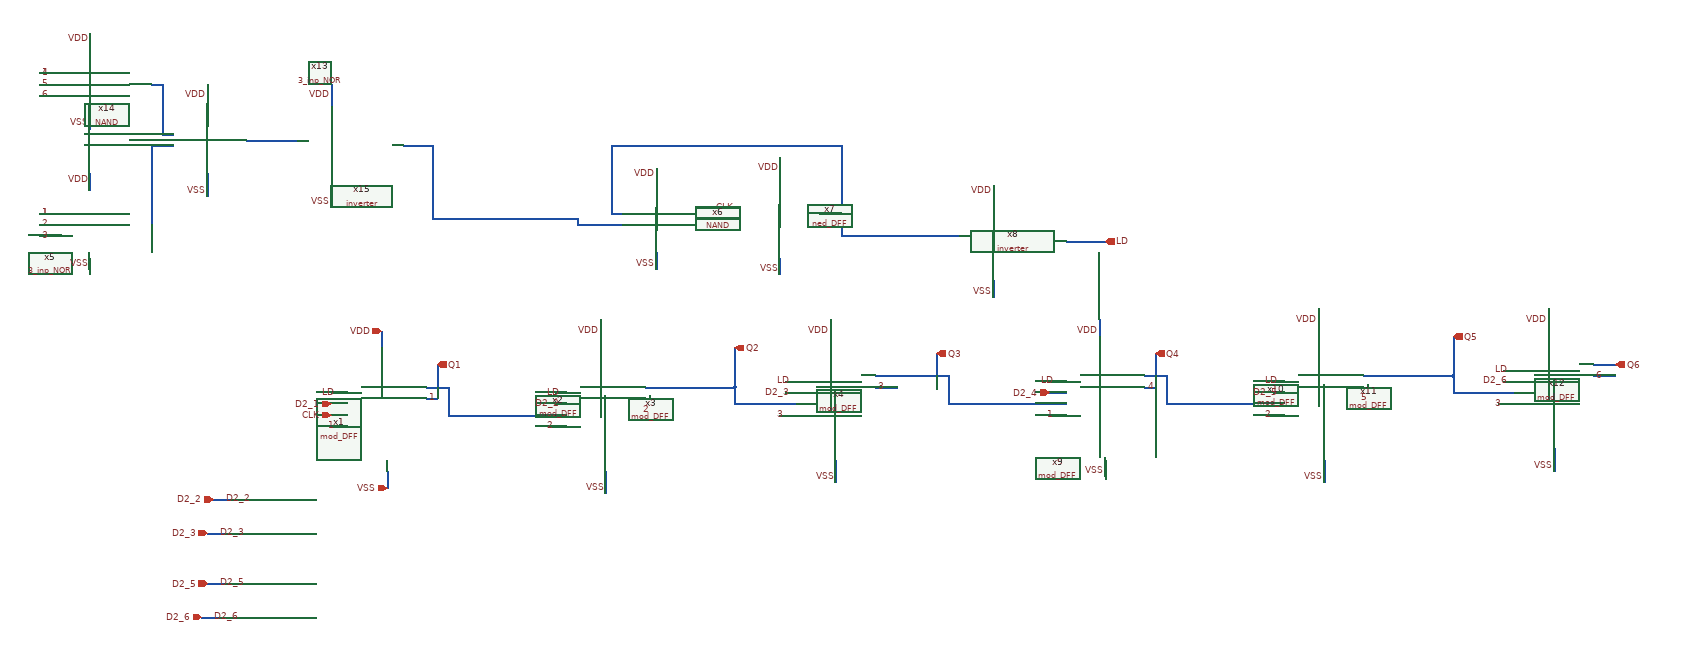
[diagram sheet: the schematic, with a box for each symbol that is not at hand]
v {xschem version=3.1.0 file_version=1.2
}
G {}
K {}
V {}
S {}
E {}
N -280 -100 -260 -100 {
lab=1}
N -450 -50 -420 -50 {
lab=1}
N -450 -90 -420 -90 {
lab=D2_1}
N -450 -70 -420 -70 {
lab=CLK}
N -360 -220 -360 -190 {
lab=VDD}
N -350 30 -350 60 {
lab=VSS}
N -280 -120 -250 -120 {
lab=Q1}
N -250 -120 -240 -120 {
lab=Q1}
N -240 -120 -240 -80 {
lab=Q1}
N -70 -70 -30 -70 {
lab=Q1}
N 860 -380 900 -380 {
lab=LD}
N -450 -110 -420 -110 {
lab=LD}
N -50 -110 -30 -110 {
lab=LD}
N -970 -430 -930 -430 {
lab=1}
N -970 -410 -930 -410 {
lab=2}
N -970 -390 -930 -390 {
lab=3}
N -880 -500 -880 -470 {
lab=VDD}
N -880 -350 -880 -330 {
lab=VSS}
N -10 -410 70 -410 {
lab=#net1}
N 460 -550 460 -390 {
lab=#net2}
N 50 -550 460 -550 {
lab=#net2}
N 50 -550 50 -430 {
lab=#net2}
N 50 -430 70 -430 {
lab=#net2}
N 460 -390 520 -390 {
lab=#net2}
N 350 -530 350 -500 {
lab=VDD}
N 130 -510 130 -480 {
lab=VDD}
N 130 -360 130 -330 {
lab=VSS}
N 350 -350 350 -320 {
lab=VSS}
N 730 -480 730 -450 {
lab=VDD}
N 30 -240 30 -190 {
lab=VDD}
N 340 -90 380 -90 {
lab=Q2}
N 520 -120 560 -120 {
lab=3}
N 110 -100 120 -100 {
lab=2}
N 120 -100 120 -70 {
lab=2}
N 360 -110 380 -110 {
lab=D2_3}
N -50 -90 -30 -90 {
lab=D2_2}
N -260 -160 -260 -120 {
lab=Q1}
N 270 -190 270 -140 {
lab=Q2}
N 520 -140 560 -140 {
lab=Q3}
N -660 80 -630 80 {
lab=D2_2}
N 440 -240 440 -210 {
lab=VDD}
N 450 10 450 50 {
lab=VSS}
N -670 140 -640 140 {
lab=D2_3}
N -60 -50 -30 -50 {
lab=2}
N 350 -70 380 -70 {
lab=3}
N 250 -440 280 -440 {
lab=CLK}
N 360 -130 380 -130 {
lab=LD}
N 270 -140 270 -130 {
lab=Q2}
N -210 -420 -20 -420 {
lab=#net1}
N -10 -420 -10 -410 {
lab=#net1}
N -20 -420 -10 -420 {
lab=#net1}
N 520 -390 670 -390 {
lab=#net2}
N 900 -380 930 -380 {
lab=LD}
N -240 -80 -240 -70 {
lab=Q1}
N -240 -70 -70 -70 {
lab=Q1}
N 110 -120 270 -120 {
lab=Q2}
N 270 -130 270 -120 {
lab=Q2}
N 270 -120 270 -90 {
lab=Q2}
N 270 -90 340 -90 {
lab=Q2}
N 200 -420 280 -420 {
lab=#net3}
N 730 -310 730 -280 {
lab=VSS}
N 40 30 40 70 {
lab=VSS}
N 420 -430 460 -430 {
lab=#net2}
N 1000 -120 1020 -120 {
lab=4}
N 830 -70 860 -70 {
lab=1}
N 830 -110 860 -110 {
lab=D2_4}
N 830 -90 860 -90 {
lab=Q3}
N 920 -240 920 -210 {
lab=VDD}
N 930 10 930 40 {
lab=#net4}
N 1000 -140 1030 -140 {
lab=Q4}
N 1030 -140 1040 -140 {
lab=Q4}
N 1040 -140 1040 -100 {
lab=Q4}
N 1210 -90 1250 -90 {
lab=Q4}
N 830 -130 860 -130 {
lab=LD}
N 1230 -130 1250 -130 {
lab=LD}
N 1310 -260 1310 -210 {
lab=VDD}
N 1620 -110 1660 -110 {
lab=Q5}
N 1800 -140 1840 -140 {
lab=6}
N 1390 -120 1400 -120 {
lab=5}
N 1400 -120 1400 -90 {
lab=5}
N 1640 -130 1660 -130 {
lab=D2_6}
N 1230 -110 1250 -110 {
lab=D2_5}
N 1020 -180 1020 -140 {
lab=Q4}
N 1550 -210 1550 -160 {
lab=Q5}
N 1800 -160 1840 -160 {
lab=Q6}
N 1720 -260 1720 -230 {
lab=VDD}
N 1730 -10 1730 30 {
lab=VSS}
N 1220 -70 1250 -70 {
lab=2}
N 1630 -90 1660 -90 {
lab=3}
N 1640 -150 1660 -150 {
lab=LD}
N 1550 -160 1550 -150 {
lab=Q5}
N 1040 -100 1040 -90 {
lab=Q4}
N 1040 -90 1210 -90 {
lab=Q4}
N 1390 -140 1550 -140 {
lab=Q5}
N 1550 -150 1550 -140 {
lab=Q5}
N 1550 -140 1550 -110 {
lab=Q5}
N 1550 -110 1620 -110 {
lab=Q5}
N 1320 10 1320 50 {
lab=VSS}
N 560 -140 650 -140 {
lab=Q3}
N 650 -90 830 -90 {
lab=Q3}
N 650 -140 650 -90 {
lab=Q3}
N 630 -180 630 -140 {
lab=Q3}
N -670 230 -640 230 {
lab=D2_5}
N -680 290 -650 290 {
lab=D2_6}
N -970 -680 -930 -680 {
lab=4}
N -970 -660 -930 -660 {
lab=5}
N -970 -640 -930 -640 {
lab=6}
N -880 -750 -880 -720 {
lab=VDD}
N -880 -600 -880 -580 {
lab=VSS}
N -770 -660 -750 -660 {
lab=#net5}
N -750 -660 -750 -570 {
lab=#net5}
N -750 -570 -730 -570 {
lab=#net5}
N -770 -550 -770 -410 {
lab=#net6}
N -770 -550 -730 -550 {
lab=#net6}
N -670 -660 -670 -620 {
lab=VDD}
N -670 -500 -670 -460 {
lab=VSS}
N -600 -560 -510 -560 {
lab=#net7}
N -450 -660 -450 -620 {
lab=VDD}
N -450 -480 -450 -440 {
lab=VSS}
N -320 -550 -270 -550 {
lab=#net1}
N -270 -550 -270 -420 {
lab=#net1}
N -270 -420 -210 -420 {
lab=#net1}
C {mod_DFF.sym} -270 -80 0 0 {name=x1}
C {mod_DFF.sym} 120 -80 0 0 {name=x2}
C {mod_DFF.sym} 120 -80 0 0 {name=x3}
C {mod_DFF.sym} 530 -100 0 0 {name=x4}
C {3_inp_NOR.sym} -560 -310 0 0 {name=x5}
C {devices/lab_wire.sym} -440 -110 0 0 {name=p2 sig_type=std_logic lab=LD}
C {devices/lab_wire.sym} -40 -110 0 0 {name=p3 sig_type=std_logic lab=LD}
C {devices/iopin.sym} -360 -220 3 0 {name=p4 lab=VDD}
C {devices/iopin.sym} -350 60 1 0 {name=p5 lab=VSS}
C {devices/lab_wire.sym} -880 -490 0 0 {name=p6 sig_type=std_logic lab=VDD}
C {devices/lab_wire.sym} -880 -340 0 0 {name=p7 sig_type=std_logic lab=VSS}
C {devices/lab_wire.sym} 130 -500 0 0 {name=p8 sig_type=std_logic lab=VDD}
C {devices/lab_wire.sym} 350 -510 0 0 {name=p9 sig_type=std_logic lab=VDD}
C {devices/lab_wire.sym} 730 -470 0 0 {name=p10 sig_type=std_logic lab=VDD}
C {devices/lab_wire.sym} 30 -220 0 0 {name=p11 sig_type=std_logic lab=VDD}
C {devices/lab_wire.sym} 130 -340 0 0 {name=p12 sig_type=std_logic lab=VSS}
C {devices/lab_wire.sym} 350 -330 0 0 {name=p13 sig_type=std_logic lab=VSS}
C {devices/lab_wire.sym} 730 -290 0 0 {name=p14 sig_type=std_logic lab=VSS}
C {devices/lab_wire.sym} 40 60 0 0 {name=p15 sig_type=std_logic lab=VSS}
C {devices/opin.sym} 630 -180 3 0 {name=p16 lab=Q3}
C {devices/opin.sym} -260 -160 3 0 {name=p17 lab=Q1}
C {devices/ipin.sym} -450 -90 0 0 {name=p18 lab=D2_1}
C {devices/ipin.sym} -660 80 0 0 {name=p19 lab=D2_2}
C {devices/lab_wire.sym} -640 80 2 0 {name=p20 sig_type=std_logic lab=D2_2}
C {devices/lab_wire.sym} -40 -90 0 0 {name=p21 sig_type=std_logic lab=D2_2}
C {devices/lab_wire.sym} 440 -220 0 0 {name=p22 sig_type=std_logic lab=VDD}
C {devices/lab_wire.sym} 450 40 0 0 {name=p23 sig_type=std_logic lab=VSS}
C {devices/ipin.sym} -670 140 0 0 {name=p24 lab=D2_3}
C {devices/lab_wire.sym} -650 140 2 0 {name=p25 sig_type=std_logic lab=D2_3}
C {devices/lab_wire.sym} 370 -110 0 0 {name=p26 sig_type=std_logic lab=D2_3}
C {devices/lab_wire.sym} -950 -430 0 0 {name=p27 sig_type=std_logic lab=1}
C {devices/lab_wire.sym} -950 -410 0 0 {name=p28 sig_type=std_logic lab=2}
C {devices/lab_wire.sym} -950 -430 0 0 {name=p29 sig_type=std_logic lab=1}
C {devices/lab_wire.sym} -950 -390 0 0 {name=p30 sig_type=std_logic lab=3}
C {devices/lab_wire.sym} -260 -100 0 0 {name=p31 sig_type=std_logic lab=1}
C {devices/lab_wire.sym} -440 -50 0 0 {name=p32 sig_type=std_logic lab=1}
C {devices/lab_wire.sym} -50 -50 0 0 {name=p33 sig_type=std_logic lab=2}
C {devices/lab_wire.sym} 120 -80 0 0 {name=p34 sig_type=std_logic lab=2}
C {devices/lab_wire.sym} 540 -120 0 0 {name=p35 sig_type=std_logic lab=3}
C {devices/lab_wire.sym} 360 -70 0 0 {name=p36 sig_type=std_logic lab=3}
C {devices/ipin.sym} -450 -70 0 0 {name=p37 lab=CLK}
C {devices/lab_wire.sym} 270 -440 0 0 {name=p38 sig_type=std_logic lab=CLK}
C {devices/opin.sym} 270 -190 3 0 {name=p39 lab=Q2}
C {devices/lab_wire.sym} 370 -130 0 0 {name=p40 sig_type=std_logic lab=LD}
C {devices/opin.sym} 930 -380 0 0 {name=p41 lab=LD}
C {NAND.sym} 220 -410 0 0 {name=x6}
C {inverter.sym} 820 -370 0 0 {name=x8}
C {ned_DFF.sym} 430 -420 0 0 {name=x7}
C {mod_DFF.sym} 1010 -100 0 0 {name=x9}
C {mod_DFF.sym} 1400 -100 0 0 {name=x10}
C {mod_DFF.sym} 1400 -100 0 0 {name=x11}
C {mod_DFF.sym} 1810 -120 0 0 {name=x12}
C {devices/lab_wire.sym} 840 -130 0 0 {name=p1 sig_type=std_logic lab=LD}
C {devices/lab_wire.sym} 1240 -130 0 0 {name=p42 sig_type=std_logic lab=LD}
C {devices/lab_wire.sym} 1310 -240 0 0 {name=p45 sig_type=std_logic lab=VDD}
C {devices/lab_wire.sym} 1320 40 0 0 {name=p46 sig_type=std_logic lab=VSS}
C {devices/opin.sym} 1840 -160 0 0 {name=p47 lab=Q6}
C {devices/opin.sym} 1020 -180 3 0 {name=p48 lab=Q4}
C {devices/ipin.sym} 830 -110 0 0 {name=p49 lab=D2_4}
C {devices/lab_wire.sym} 1720 -240 0 0 {name=p51 sig_type=std_logic lab=VDD}
C {devices/lab_wire.sym} 1730 20 0 0 {name=p52 sig_type=std_logic lab=VSS}
C {devices/lab_wire.sym} 1020 -120 0 0 {name=p54 sig_type=std_logic lab=4}
C {devices/lab_wire.sym} 840 -70 0 0 {name=p55 sig_type=std_logic lab=1}
C {devices/lab_wire.sym} 1230 -70 0 0 {name=p56 sig_type=std_logic lab=2}
C {devices/lab_wire.sym} 1400 -100 0 0 {name=p57 sig_type=std_logic lab=5}
C {devices/lab_wire.sym} 1820 -140 0 0 {name=p58 sig_type=std_logic lab=6}
C {devices/lab_wire.sym} 1640 -90 0 0 {name=p59 sig_type=std_logic lab=3}
C {devices/opin.sym} 1550 -210 3 0 {name=p61 lab=Q5}
C {devices/lab_wire.sym} 1650 -150 0 0 {name=p62 sig_type=std_logic lab=LD}
C {devices/ipin.sym} -670 230 0 0 {name=p60 lab=D2_5}
C {devices/lab_wire.sym} -650 230 2 0 {name=p63 sig_type=std_logic lab=D2_5}
C {devices/ipin.sym} -680 290 0 0 {name=p64 lab=D2_6}
C {devices/lab_wire.sym} -660 290 2 0 {name=p65 sig_type=std_logic lab=D2_6}
C {devices/lab_wire.sym} 1240 -110 0 0 {name=p50 sig_type=std_logic lab=D2_5}
C {devices/lab_wire.sym} 1650 -130 0 0 {name=p53 sig_type=std_logic lab=D2_6}
C {3_inp_NOR.sym} -560 -560 0 0 {name=x13}
C {devices/lab_wire.sym} -670 -640 0 0 {name=p66 sig_type=std_logic lab=VDD}
C {devices/lab_wire.sym} -880 -590 0 0 {name=p67 sig_type=std_logic lab=VSS}
C {devices/lab_wire.sym} -950 -680 0 0 {name=p68 sig_type=std_logic lab=4}
C {devices/lab_wire.sym} -950 -660 0 0 {name=p69 sig_type=std_logic lab=5}
C {devices/lab_wire.sym} -950 -680 0 0 {name=p70 sig_type=std_logic lab=1}
C {devices/lab_wire.sym} -950 -640 0 0 {name=p71 sig_type=std_logic lab=6}
C {NAND.sym} -580 -550 0 0 {name=x14}
C {devices/lab_wire.sym} -670 -470 0 0 {name=p72 sig_type=std_logic lab=VSS}
C {devices/lab_wire.sym} -880 -740 0 0 {name=p73 sig_type=std_logic lab=VDD}
C {inverter.sym} -360 -540 0 0 {name=x15}
C {devices/lab_wire.sym} -450 -640 0 0 {name=p74 sig_type=std_logic lab=VDD}
C {devices/lab_wire.sym} -450 -450 0 0 {name=p75 sig_type=std_logic lab=VSS}
C {devices/lab_wire.sym} 920 -220 0 0 {name=p43 sig_type=std_logic lab=VDD}
C {devices/lab_wire.sym} 930 30 0 0 {name=p44 sig_type=std_logic lab=VSS}
